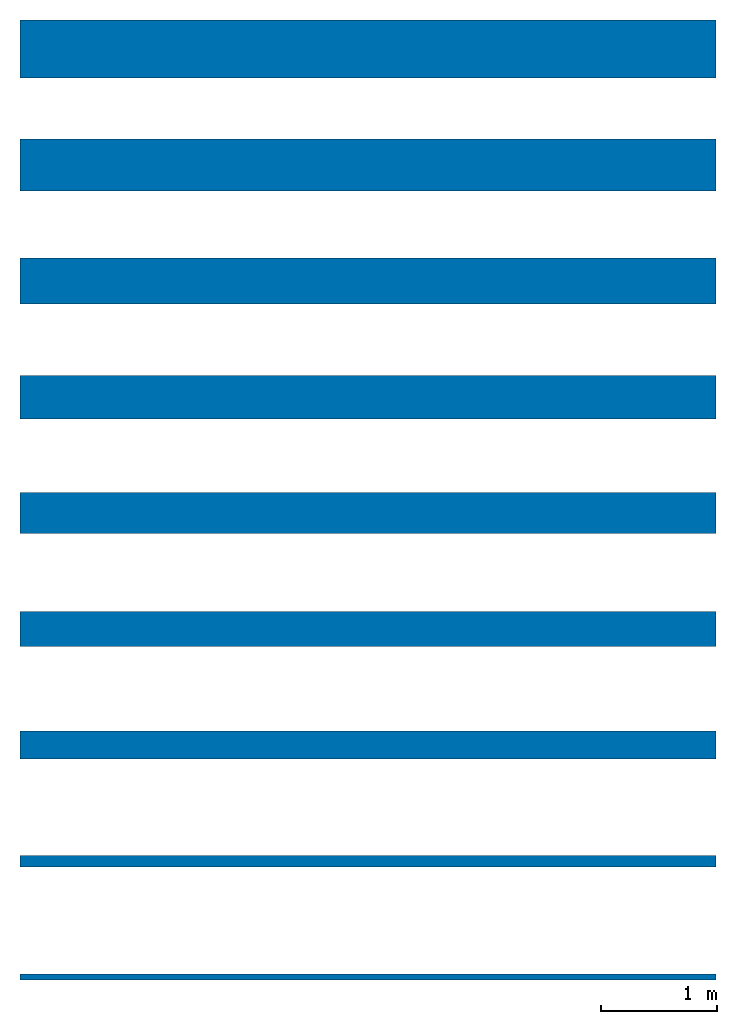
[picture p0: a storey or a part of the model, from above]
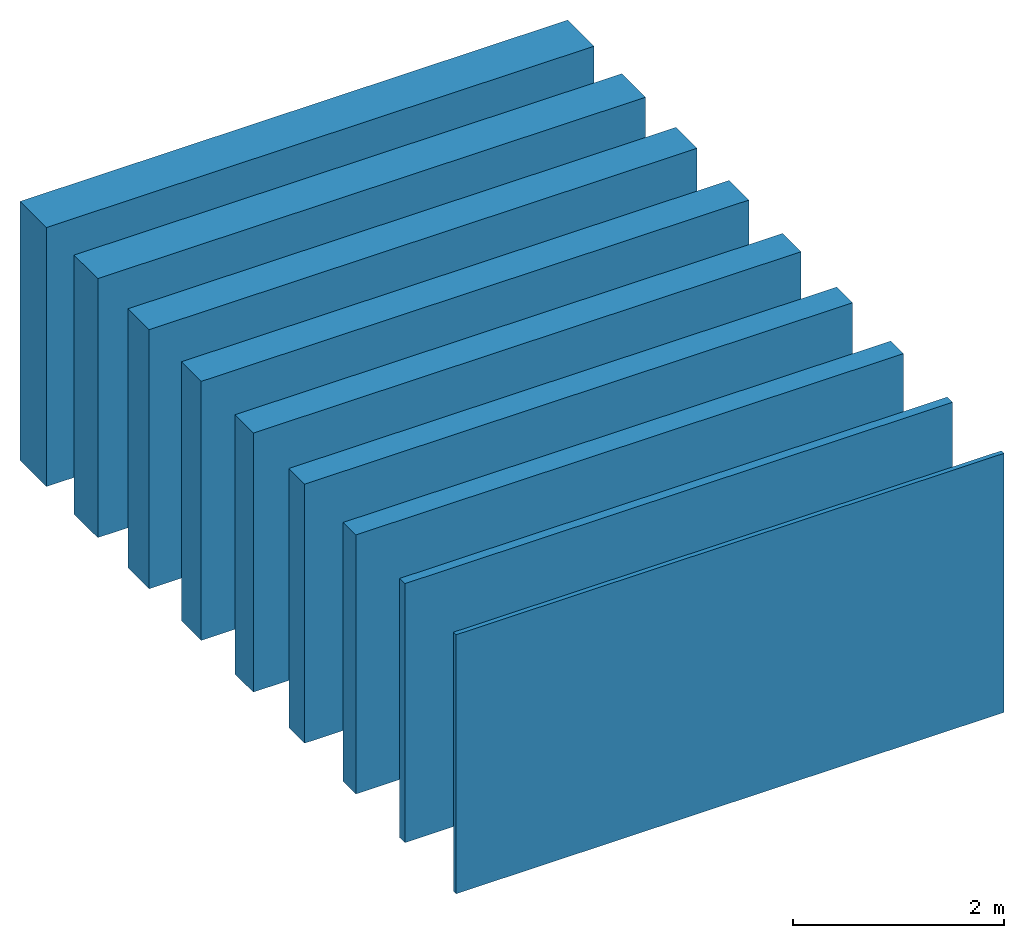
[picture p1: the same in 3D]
Properties of the parts of a building model (IFC2X3)

# File
Description: ViewDefinition [CoordinationView]
File name: Numero
Time: 2019-05-03T09:51:13
Written by: The EXPRESS Data Manager Version 5.02.0100.07 : 28 Aug 2013
Made in: 20150220_1215(x64) - Exporter 16.0.428.0 - Default UI
Comment: STEP Physical File produced by: The EXPRESS Data Manager Version 5.02.0100.07 : 28 Aug 2013 * Module: EDMstepFileFactory/EDMstandAlone * Creation date: Fri May 03 09:51:13 2019 * Host: HP-RS * Database: C:\Users\EKORU_~1\AppData\Local\Temp\{6F6A4437-CCBD-47AC-A56C-AE0055DA8219}\ifc * Database version: 5507 * Database creation date: Fri May 03 09:51:12 2019 * Schema: IFC2X3 * Model: DataRepository.ifc * Model creation date: Fri May 03 09:51:12 2019 * Header model: DataRepository.ifc_HeaderModel * Header model creation date: Fri May 03 09:51:12 2019 * EDMuser: sdai-user * EDMgroup: sdai-group * License ID and type: 5605 : Permanent license. Expiry date: * EDMstepFileFactory options: 020000

# IfcProject, Numero
LongName: Nome; Phase: Stato

# IfcSite, Default
RefLatitude: 41, 47, 59, 999999; RefLongitude: 12, 35, 59, 999999; RefElevation: 0 mm
Altro - Categoria: Informazioni sul progetto; Data di consegna del progetto: Data; Indirizzo del progetto: Immettere l'indirizzo; Nome del cliente: Proprietario; Nome del progetto: Nome; Numero del progetto: Numero; Stato del progetto: Stato

# IfcBuilding
Pset_BuildingCommon - NumberOfStoreys: 1
Altro - Categoria: Informazioni sul progetto; Data di consegna del progetto: Data; Indirizzo del progetto: Immettere l'indirizzo; Nome del cliente: Proprietario; Nome del progetto: Nome; Numero del progetto: Numero; Stato del progetto: Stato

# IfcBuildingStorey, Livello 1
LongName: Livello 1; Elevation: 0 mm
Vincoli - Base quota altimetrica: Punto base progetto; Quota altimetrica: 0 mm
Altro - Categoria: Livelli; Famiglia: Livello: Estremità 8 mm; Famiglia e tipo: Livello: Estremità 8 mm; ID tipo: Livello: Estremità 8 mm; Tipo: Livello: Estremità 8 mm; Nome famiglia: Livello
Dati identità - Strutturale: no; Nome: Livello 1; Piano edificio: yes; Nome del tipo: Estremità 8 mm
Dimensioni - Altezza di calcolo: 0 mm
Grafica - Colore: 0; Modello di linea: Centro; Simbolo: Estremità del livello - Cerchio: Estremità del livello - Cerchio; Simbolo a estremità 1 per default: no; Simbolo a estremità 2 per default: yes; Spessore di linea: 1

# IfcWallStandardCase: Muro di base:GASBETON Active sp. 100 mm, Muro di base:GASBETON Active sp. 100 mm:127299
In: Livello 1
Type - PredefinedType: STANDARD; Material: GASBETON Active 100 mm
Type - Altro - Categoria: Muri; Nome famiglia: Muro di base
Type - Costruzione - Funzione: Esterno; Ripiegatura agli inserti: Non ripiegare; Ripiegatura alle estremità: Nessuno; Larghezza: 100 mm
Type - Dati identità - Descrizione: muratura formata da blocchi GASBETON Active, densità a secco del singolo blocco 300 kg/mc; Installation Guide: http://www.gasbeton.it/wp-content/uploads/2017/11/GASBETON-Guida-alla-progettazione.pdf; Modello: Muratura Gasbeton Active; Nome del tipo: GASBETON Active sp. 100 mm; Product data url: www.gasbeton.it; Produttore: EKORU s.r.l.; Resistenza al fuoco: Euroclasse A1; Technical data sheet: http://www.gasbeton.it/download/active/; URL: http://www.ekoru.it/; Youtube channel: https://www.youtube.com/user/bacchispa
Type - Generale - Edition number: 1; Manufacturer country: Italy; Manufacturer name: EKORU s.r.l.; Product family: walls
Type - Grafica - Colore del retino a dettaglio basso: 0
Type - Materiali e finiture - Materiale strutturale: GASBETON Active; Material main: Autoclaved Aerated Concrete (AAC)
Type - Proprietà analitiche - Ruvidità: 2; Assorbimento: 0.7; Coefficiente di scambio termico (U): 0.7; Massa termica: 30000; Resistenza termica (R): 1.42857
Altro - Famiglia: Muro di base: GASBETON Active sp. 100 mm; Famiglia e tipo: Muro di base: GASBETON Active sp. 100 mm; ID tipo: Muro di base: GASBETON Active sp. 100 mm; Tipo: Muro di base: GASBETON Active sp. 100 mm
Dimensioni - Area: 18 m2; Lunghezza: 6000 mm; Volume: 1.8 m3
Fasi - Fase di creazione: Fase 1
Strutturale - Attiva modello analitico: no; Strutturale: no; Utilizzo strutturale: Non portante
Vincoli - Delimita il locale: yes; Distanza estensione base: 0 mm; Distanza estensione superiore: 0 mm; La base è associata: no; La parte superiore è associata: no; Linea di ubicazione: Linea d'asse del muro; Offset base: 0 mm; Offset superiore: 0 mm; Relativo a massa: no; Vincolo di base: Livello: Livello 1; Vincolo parte superiore: Livello: Livello 2; Altezza non collegata: 3000 mm
Pset_WallCommon - LoadBearing: no; ExtendToStructure: no; IsExternal: yes; Reference: GASBETON Active sp. 100 mm; FireRating: Euroclasse A1; ThermalTransmittance: 0.7 kg/K/s3
Pset_ManufacturerTypeInformation - Manufacturer: EKORU s.r.l.

# IfcWallStandardCase: Muro di base:GASBETON Active sp. 240 mm, Muro di base:GASBETON Active sp. 240 mm:127225
In: Livello 1
Type - PredefinedType: STANDARD; Material: GASBETON Active 240 mm
Type - Altro - Categoria: Muri; Nome famiglia: Muro di base
Type - Costruzione - Funzione: Esterno; Ripiegatura agli inserti: Non ripiegare; Ripiegatura alle estremità: Nessuno; Larghezza: 240 mm
Type - Dati identità - Descrizione: muratura formata da blocchi GASBETON Active, densità a secco del singolo blocco 300 kg/mc; Installation Guide: http://www.gasbeton.it/wp-content/uploads/2017/11/GASBETON-Guida-alla-progettazione.pdf; Modello: Muratura Gasbeton Active; Nome del tipo: GASBETON Active sp. 240 mm; Product data url: https://www.bimobject.com/en/ekoru/product/gasbeton-active-basic; Produttore: EKORU s.r.l.; Resistenza al fuoco: EI 240; Euroclasse A1; Technical data sheet: http://www.gasbeton.it/download/active/; URL: http://www.ekoru.it/; Youtube channel: https://www.youtube.com/user/bacchispa
Type - Generale - Edition number: 1; Manufacturer country: Italy; Manufacturer name: EKORU s.r.l.; Product family: walls
Type - Grafica - Colore del retino a dettaglio basso: 0
Type - Materiali e finiture - Materiale strutturale: GASBETON Active; Material main: Autoclaved Aerated Concrete (AAC)
Type - Proprietà analitiche - Ruvidità: 2; Assorbimento: 0.7; Coefficiente di scambio termico (U): 0.291667; Massa termica: 72000; Resistenza termica (R): 3.42857
Altro - Famiglia: Muro di base: GASBETON Active sp. 240 mm; Famiglia e tipo: Muro di base: GASBETON Active sp. 240 mm; ID tipo: Muro di base: GASBETON Active sp. 240 mm; Tipo: Muro di base: GASBETON Active sp. 240 mm
Dimensioni - Area: 18 m2; Lunghezza: 6000 mm; Volume: 4.32 m3
Fasi - Fase di creazione: Fase 1
Strutturale - Attiva modello analitico: no; Strutturale: no; Utilizzo strutturale: Non portante
Vincoli - Delimita il locale: yes; Distanza estensione base: 0 mm; Distanza estensione superiore: 0 mm; La base è associata: no; La parte superiore è associata: no; Linea di ubicazione: Linea d'asse del muro; Offset base: 0 mm; Offset superiore: 0 mm; Relativo a massa: no; Vincolo di base: Livello: Livello 1; Vincolo parte superiore: Livello: Livello 2; Altezza non collegata: 3000 mm
Pset_WallCommon - LoadBearing: no; ExtendToStructure: no; IsExternal: yes; Reference: GASBETON Active sp. 240 mm; FireRating: EI 240; Euroclasse A1; ThermalTransmittance: 0.291667 kg/K/s3
Pset_ManufacturerTypeInformation - Manufacturer: EKORU s.r.l.

# IfcWallStandardCase: Muro di base:GASBETON Active sp. 300 mm, Muro di base:GASBETON Active sp. 300 mm:127094
In: Livello 1
Type - PredefinedType: STANDARD; Material: GASBETON Active 300 mm
Type - Altro - Categoria: Muri; Nome famiglia: Muro di base
Type - Costruzione - Funzione: Esterno; Ripiegatura agli inserti: Non ripiegare; Ripiegatura alle estremità: Nessuno; Larghezza: 300 mm
Type - Dati identità - Descrizione: muratura formata da blocchi GASBETON Active, densità a secco del singolo blocco 300 kg/mc; Installation Guide: http://www.gasbeton.it/wp-content/uploads/2017/11/GASBETON-Guida-alla-progettazione.pdf; Modello: Muratura Gasbeton Active; Nome del tipo: GASBETON Active sp. 300 mm; Product data url: https://www.bimobject.com/en/ekoru/product/gasbeton-active-basic; Produttore: EKORU s.r.l.; Resistenza al fuoco: EI 240; Euroclasse A1; Technical data sheet: http://www.gasbeton.it/download/active/; URL: http://www.ekoru.it/; Youtube channel: https://www.youtube.com/user/bacchispa
Type - Generale - Edition number: 1; Manufacturer country: Italy; Manufacturer name: EKORU s.r.l.; Product family: walls
Type - Grafica - Colore del retino a dettaglio basso: 0
Type - Materiali e finiture - Materiale strutturale: GASBETON Active; Material main: Autoclaved Aerated Concrete (AAC)
Type - Proprietà analitiche - Ruvidità: 2; Assorbimento: 0.7; Coefficiente di scambio termico (U): 0.233333; Massa termica: 90000; Resistenza termica (R): 4.28571
Altro - Famiglia: Muro di base: GASBETON Active sp. 300 mm; Famiglia e tipo: Muro di base: GASBETON Active sp. 300 mm; ID tipo: Muro di base: GASBETON Active sp. 300 mm; Tipo: Muro di base: GASBETON Active sp. 300 mm
Dimensioni - Area: 18 m2; Lunghezza: 6000 mm; Volume: 5.4 m3
Fasi - Fase di creazione: Fase 1
Strutturale - Attiva modello analitico: no; Strutturale: no; Utilizzo strutturale: Non portante
Vincoli - Delimita il locale: yes; Distanza estensione base: 0 mm; Distanza estensione superiore: 0 mm; La base è associata: no; La parte superiore è associata: no; Linea di ubicazione: Linea d'asse del muro; Offset base: 0 mm; Offset superiore: 0 mm; Relativo a massa: no; Vincolo di base: Livello: Livello 1; Vincolo parte superiore: Livello: Livello 2; Altezza non collegata: 3000 mm
Pset_WallCommon - LoadBearing: no; ExtendToStructure: no; IsExternal: yes; Reference: GASBETON Active sp. 300 mm; FireRating: EI 240; Euroclasse A1; ThermalTransmittance: 0.233333 kg/K/s3
Pset_ManufacturerTypeInformation - Manufacturer: EKORU s.r.l.

# IfcWallStandardCase: Muro di base:GASBETON Active sp. 350 mm, Muro di base:GASBETON Active sp. 350 mm:126939
In: Livello 1
Type - PredefinedType: STANDARD; Material: GASBETON Active 350 mm
Type - Altro - Categoria: Muri; Nome famiglia: Muro di base
Type - Costruzione - Funzione: Esterno; Ripiegatura agli inserti: Non ripiegare; Ripiegatura alle estremità: Nessuno; Larghezza: 350 mm
Type - Dati identità - Descrizione: muratura formata da blocchi GASBETON Active, densità a secco del singolo blocco 300 kg/mc; Installation Guide: http://www.gasbeton.it/wp-content/uploads/2017/11/GASBETON-Guida-alla-progettazione.pdf; Modello: Muratura Gasbeton Active; Nome del tipo: GASBETON Active sp. 350 mm; Product data url: www.gasbeton.it; Produttore: EKORU s.r.l.; Resistenza al fuoco: EI 240; Euroclasse A1; Technical data sheet: http://www.gasbeton.it/download/active/; URL: http://www.ekoru.it/; Youtube channel: https://www.youtube.com/user/bacchispa
Type - Generale - Edition number: 1; Manufacturer country: Italy; Manufacturer name: EKORU s.r.l.; Product family: walls
Type - Grafica - Colore del retino a dettaglio basso: 0
Type - Materiali e finiture - Materiale strutturale: GASBETON Active; Material main: Autoclaved Aerated Concrete (AAC)
Type - Proprietà analitiche - Ruvidità: 2; Assorbimento: 0.7; Coefficiente di scambio termico (U): 0.2; Massa termica: 105000; Resistenza termica (R): 5
Altro - Famiglia: Muro di base: GASBETON Active sp. 350 mm; Famiglia e tipo: Muro di base: GASBETON Active sp. 350 mm; ID tipo: Muro di base: GASBETON Active sp. 350 mm; Tipo: Muro di base: GASBETON Active sp. 350 mm
Dimensioni - Area: 18 m2; Lunghezza: 6000 mm; Volume: 6.3 m3
Fasi - Fase di creazione: Fase 1
Strutturale - Attiva modello analitico: no; Strutturale: no; Utilizzo strutturale: Non portante
Vincoli - Delimita il locale: yes; Distanza estensione base: 0 mm; Distanza estensione superiore: 0 mm; La base è associata: no; La parte superiore è associata: no; Linea di ubicazione: Linea d'asse del muro; Offset base: 0 mm; Offset superiore: 0 mm; Relativo a massa: no; Vincolo di base: Livello: Livello 1; Vincolo parte superiore: Livello: Livello 2; Altezza non collegata: 3000 mm
Pset_WallCommon - LoadBearing: no; ExtendToStructure: no; IsExternal: yes; Reference: GASBETON Active sp. 350 mm; FireRating: EI 240; Euroclasse A1; ThermalTransmittance: 0.2 kg/K/s3
Pset_ManufacturerTypeInformation - Manufacturer: EKORU s.r.l.

# IfcWallStandardCase: Muro di base:GASBETON Active sp. 375 mm, Muro di base:GASBETON Active sp. 375 mm:126730
In: Livello 1
Type - PredefinedType: STANDARD; Material: GASBETON Active 375 mm
Type - Altro - Categoria: Muri; Nome famiglia: Muro di base
Type - Costruzione - Funzione: Esterno; Ripiegatura agli inserti: Non ripiegare; Ripiegatura alle estremità: Nessuno; Larghezza: 375 mm
Type - Dati identità - Descrizione: muratura formata da blocchi GASBETON Active, densità a secco del singolo blocco 300 kg/mc; Installation Guide: http://www.gasbeton.it/wp-content/uploads/2017/11/GASBETON-Guida-alla-progettazione.pdf; Modello: Muratura Gasbeton Active; Nome del tipo: GASBETON Active sp. 375 mm; Product data url: https://www.bimobject.com/en/ekoru/product/gasbeton-active-basic; Produttore: EKORU s.r.l.; Resistenza al fuoco: EI 240; Euroclasse A1; Technical data sheet: http://www.gasbeton.it/download/active/; URL: http://www.ekoru.it/; Youtube channel: https://www.youtube.com/user/bacchispa
Type - Generale - Edition number: 1; Manufacturer country: Italy; Manufacturer name: EKORU s.r.l.; Product family: walls
Type - Grafica - Colore del retino a dettaglio basso: 0
Type - Materiali e finiture - Materiale strutturale: GASBETON Active; Material main: Autoclaved Aerated Concrete (AAC)
Type - Proprietà analitiche - Ruvidità: 2; Assorbimento: 0.7; Coefficiente di scambio termico (U): 0.186667; Massa termica: 112500; Resistenza termica (R): 5.35714
Altro - Famiglia: Muro di base: GASBETON Active sp. 375 mm; Famiglia e tipo: Muro di base: GASBETON Active sp. 375 mm; ID tipo: Muro di base: GASBETON Active sp. 375 mm; Tipo: Muro di base: GASBETON Active sp. 375 mm
Dimensioni - Area: 18 m2; Lunghezza: 6000 mm; Volume: 6.75 m3
Fasi - Fase di creazione: Fase 1
Strutturale - Attiva modello analitico: no; Strutturale: no; Utilizzo strutturale: Non portante
Vincoli - Delimita il locale: yes; Distanza estensione base: 0 mm; Distanza estensione superiore: 0 mm; La base è associata: no; La parte superiore è associata: no; Linea di ubicazione: Linea d'asse del muro; Offset base: 0 mm; Offset superiore: 0 mm; Relativo a massa: no; Vincolo di base: Livello: Livello 1; Vincolo parte superiore: Livello: Livello 2; Altezza non collegata: 3000 mm
Pset_WallCommon - LoadBearing: no; ExtendToStructure: no; IsExternal: yes; Reference: GASBETON Active sp. 375 mm; FireRating: EI 240; Euroclasse A1; ThermalTransmittance: 0.186667 kg/K/s3
Pset_ManufacturerTypeInformation - Manufacturer: EKORU s.r.l.

# IfcWallStandardCase: Muro di base:GASBETON Active sp. 400 mm, Muro di base:GASBETON Active sp. 400 mm:126726
In: Livello 1
Type - PredefinedType: STANDARD; Material: GASBETON Active 400 mm
Type - Altro - Categoria: Muri; Nome famiglia: Muro di base
Type - Costruzione - Funzione: Esterno; Ripiegatura agli inserti: Non ripiegare; Ripiegatura alle estremità: Nessuno; Larghezza: 400 mm
Type - Dati identità - Descrizione: muratura formata da blocchi GASBETON Active, densità a secco del singolo blocco 300 kg/mc; Installation Guide: http://www.gasbeton.it/wp-content/uploads/2017/11/GASBETON-Guida-alla-progettazione.pdf; Modello: Muratura Gasbeton Active; Nome del tipo: GASBETON Active sp. 400 mm; Product data url: www.gasbeton.it; Produttore: EKORU s.r.l.; Resistenza al fuoco: EI 240; Euroclasse A1; Technical data sheet: http://www.gasbeton.it/download/active/; URL: http://www.ekoru.it/; Youtube channel: https://www.youtube.com/user/bacchispa
Type - Generale - Edition number: 1; Manufacturer country: Italy; Manufacturer name: EKORU s.r.l.; Product family: walls
Type - Grafica - Colore del retino a dettaglio basso: 0
Type - Materiali e finiture - Materiale strutturale: GASBETON Active; Material main: Autoclaved Aerated Concrete (AAC)
Type - Proprietà analitiche - Ruvidità: 2; Assorbimento: 0.7; Coefficiente di scambio termico (U): 0.175; Massa termica: 120000; Resistenza termica (R): 5.71429
Altro - Famiglia: Muro di base: GASBETON Active sp. 400 mm; Famiglia e tipo: Muro di base: GASBETON Active sp. 400 mm; ID tipo: Muro di base: GASBETON Active sp. 400 mm; Tipo: Muro di base: GASBETON Active sp. 400 mm
Dimensioni - Area: 18 m2; Lunghezza: 6000 mm; Volume: 7.2 m3
Fasi - Fase di creazione: Fase 1
Strutturale - Attiva modello analitico: no; Strutturale: no; Utilizzo strutturale: Non portante
Vincoli - Delimita il locale: yes; Distanza estensione base: 0 mm; Distanza estensione superiore: 0 mm; La base è associata: no; La parte superiore è associata: no; Linea di ubicazione: Linea d'asse del muro; Offset base: 0 mm; Offset superiore: 0 mm; Relativo a massa: no; Vincolo di base: Livello: Livello 1; Vincolo parte superiore: Livello: Livello 2; Altezza non collegata: 3000 mm
Pset_WallCommon - LoadBearing: no; ExtendToStructure: no; IsExternal: yes; Reference: GASBETON Active sp. 400 mm; FireRating: EI 240; Euroclasse A1; ThermalTransmittance: 0.175 kg/K/s3
Pset_ManufacturerTypeInformation - Manufacturer: EKORU s.r.l.

# IfcWallStandardCase: Muro di base:GASBETON Active sp. 450 mm, Muro di base:GASBETON Active sp. 450 mm:126642
In: Livello 1
Type - PredefinedType: STANDARD; Material: GASBETON Active 450 mm
Type - Altro - Categoria: Muri; Nome famiglia: Muro di base
Type - Costruzione - Funzione: Esterno; Ripiegatura agli inserti: Non ripiegare; Ripiegatura alle estremità: Nessuno; Larghezza: 450 mm
Type - Dati identità - Descrizione: muratura formata da blocchi GASBETON Active, densità a secco del singolo blocco 300 kg/mc; Installation Guide: http://www.gasbeton.it/wp-content/uploads/2017/11/GASBETON-Guida-alla-progettazione.pdf; Modello: Muratura Gasbeton Active; Nome del tipo: GASBETON Active sp. 450 mm; Product data url: https://www.bimobject.com/en/ekoru/product/gasbeton-active-basic; Produttore: EKORU s.r.l.; Resistenza al fuoco: EI 240; Euroclasse A1; Technical data sheet: http://www.gasbeton.it/download/active/; URL: http://www.ekoru.it/; Youtube channel: https://www.youtube.com/user/bacchispa
Type - Generale - Edition number: 1; Manufacturer country: Italy; Manufacturer name: EKORU s.r.l.; Product family: walls
Type - Grafica - Colore del retino a dettaglio basso: 0
Type - Materiali e finiture - Materiale strutturale: GASBETON Active; Material main: Autoclaved Aerated Concrete (AAC)
Type - Proprietà analitiche - Ruvidità: 2; Assorbimento: 0.7; Coefficiente di scambio termico (U): 0.155556; Massa termica: 135000; Resistenza termica (R): 6.42857
Altro - Famiglia: Muro di base: GASBETON Active sp. 450 mm; Famiglia e tipo: Muro di base: GASBETON Active sp. 450 mm; ID tipo: Muro di base: GASBETON Active sp. 450 mm; Tipo: Muro di base: GASBETON Active sp. 450 mm
Dimensioni - Area: 18 m2; Lunghezza: 6000 mm; Volume: 8.1 m3
Fasi - Fase di creazione: Fase 1
Strutturale - Attiva modello analitico: no; Strutturale: no; Utilizzo strutturale: Non portante
Vincoli - Delimita il locale: yes; Distanza estensione base: 0 mm; Distanza estensione superiore: 0 mm; La base è associata: no; La parte superiore è associata: no; Linea di ubicazione: Linea d'asse del muro; Offset base: 0 mm; Offset superiore: 0 mm; Relativo a massa: no; Vincolo di base: Livello: Livello 1; Vincolo parte superiore: Livello: Livello 2; Altezza non collegata: 3000 mm
Pset_WallCommon - LoadBearing: no; ExtendToStructure: no; IsExternal: yes; Reference: GASBETON Active sp. 450 mm; FireRating: EI 240; Euroclasse A1; ThermalTransmittance: 0.155556 kg/K/s3
Pset_ManufacturerTypeInformation - Manufacturer: EKORU s.r.l.

# IfcWallStandardCase: Muro di base:GASBETON Active sp. 50 mm, Muro di base:GASBETON Active sp. 50 mm:129725
In: Livello 1
Type - PredefinedType: STANDARD; Material: GASBETON Active 50 mm
Type - Altro - Categoria: Muri; Nome famiglia: Muro di base
Type - Costruzione - Funzione: Esterno; Ripiegatura agli inserti: Non ripiegare; Ripiegatura alle estremità: Nessuno; Larghezza: 50 mm
Type - Dati identità - Descrizione: muratura formata da blocchi GASBETON Active, densità a secco del singolo blocco 300 kg/mc; Installation Guide: http://www.gasbeton.it/wp-content/uploads/2017/11/GASBETON-Guida-alla-progettazione.pdf; Modello: Muratura Gasbeton Active; Nome del tipo: GASBETON Active sp. 50 mm; Product data url: https://www.bimobject.com/en/ekoru/product/gasbeton-active-basic; Produttore: EKORU s.r.l.; Resistenza al fuoco: Euroclasse A1; Technical data sheet: http://www.gasbeton.it/download/active/; URL: http://www.ekoru.it/; Youtube channel: https://www.youtube.com/user/bacchispa
Type - Generale - Edition number: 1; Manufacturer country: Italy; Manufacturer name: EKORU s.r.l.; Product family: walls
Type - Grafica - Colore del retino a dettaglio basso: 0
Type - Materiali e finiture - Materiale strutturale: GASBETON Active; Material main: Autoclaved Aerated Concrete (AAC)
Type - Proprietà analitiche - Ruvidità: 2; Assorbimento: 0.7; Coefficiente di scambio termico (U): 1.4; Massa termica: 15000; Resistenza termica (R): 0.714286
Altro - Famiglia: Muro di base: GASBETON Active sp. 50 mm; Famiglia e tipo: Muro di base: GASBETON Active sp. 50 mm; ID tipo: Muro di base: GASBETON Active sp. 50 mm; Tipo: Muro di base: GASBETON Active sp. 50 mm
Dimensioni - Area: 18 m2; Lunghezza: 6000 mm; Volume: 0.9 m3
Fasi - Fase di creazione: Fase 1
Strutturale - Attiva modello analitico: no; Strutturale: no; Utilizzo strutturale: Non portante
Vincoli - Delimita il locale: yes; Distanza estensione base: 0 mm; Distanza estensione superiore: 0 mm; La base è associata: no; La parte superiore è associata: no; Linea di ubicazione: Linea d'asse del muro; Offset base: 0 mm; Offset superiore: 0 mm; Relativo a massa: no; Vincolo di base: Livello: Livello 1; Vincolo parte superiore: Livello: Livello 2; Altezza non collegata: 3000 mm
Pset_WallCommon - LoadBearing: no; ExtendToStructure: no; IsExternal: yes; Reference: GASBETON Active sp. 50 mm; FireRating: Euroclasse A1; ThermalTransmittance: 1.4 kg/K/s3
Pset_ManufacturerTypeInformation - Manufacturer: EKORU s.r.l.

# IfcWallStandardCase: Muro di base:GASBETON Active sp. 500 mm, Muro di base:GASBETON Active sp. 500 mm:125781
In: Livello 1
Type - PredefinedType: STANDARD; Material: GASBETON Active 500 mm
Type - Altro - Categoria: Muri; Nome famiglia: Muro di base
Type - Costruzione - Funzione: Esterno; Larghezza: 500 mm; Ripiegatura agli inserti: Non ripiegare; Ripiegatura alle estremità: Nessuno
Type - Dati identità - Descrizione: muratura formata da blocchi GASBETON Active, densità a secco del singolo blocco 300 kg/mc; Installation Guide: http://www.gasbeton.it/wp-content/uploads/2017/11/GASBETON-Guida-alla-progettazione.pdf; Modello: Muratura Gasbeton Active; Nome del tipo: GASBETON Active sp. 500 mm; Product data url: www.gasbeton.it; Produttore: EKORU s.r.l.; Resistenza al fuoco: EI 240; Euroclasse A1; Technical data sheet: http://www.gasbeton.it/download/active/; URL: http://www.ekoru.it/; Youtube channel: https://www.youtube.com/user/bacchispa
Type - Generale - Edition number: 1; Manufacturer country: Italy; Manufacturer name: EKORU s.r.l.; Product family: walls
Type - Grafica - Colore del retino a dettaglio basso: 0
Type - Materiali e finiture - Materiale strutturale: GASBETON Active; Material main: Autoclaved Aerated Concrete (AAC)
Type - Proprietà analitiche - Assorbimento: 0.7; Coefficiente di scambio termico (U): 0.14; Massa termica: 150000; Resistenza termica (R): 7.14286; Ruvidità: 2
Altro - Famiglia: Muro di base: GASBETON Active sp. 500 mm; Famiglia e tipo: Muro di base: GASBETON Active sp. 500 mm; ID tipo: Muro di base: GASBETON Active sp. 500 mm; Tipo: Muro di base: GASBETON Active sp. 500 mm
Dimensioni - Area: 18 m2; Lunghezza: 6000 mm; Volume: 9 m3
Fasi - Fase di creazione: Fase 1
Strutturale - Attiva modello analitico: no; Strutturale: no; Utilizzo strutturale: Non portante
Vincoli - Altezza non collegata: 3000 mm; Delimita il locale: yes; Distanza estensione base: 0 mm; Distanza estensione superiore: 0 mm; La base è associata: no; La parte superiore è associata: no; Linea di ubicazione: Linea d'asse del muro; Offset base: 0 mm; Offset superiore: 0 mm; Relativo a massa: no; Vincolo di base: Livello: Livello 1; Vincolo parte superiore: Livello: Livello 2
Pset_WallCommon - Reference: GASBETON Active sp. 500 mm; LoadBearing: no; ExtendToStructure: no; IsExternal: yes; FireRating: EI 240; Euroclasse A1; ThermalTransmittance: 0.14 kg/K/s3
Pset_ManufacturerTypeInformation - Manufacturer: EKORU s.r.l.
